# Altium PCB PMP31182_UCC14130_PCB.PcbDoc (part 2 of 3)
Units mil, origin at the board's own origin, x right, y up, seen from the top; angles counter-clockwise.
Board outline 4922 x 2399 mil, 4 copper layers (Top Layer, Signal Layer 1, Signal Layer 2, Bottom Layer), stack 77.9 mil thick; 154 components, 84 nets, 539 pads, 732 vias.

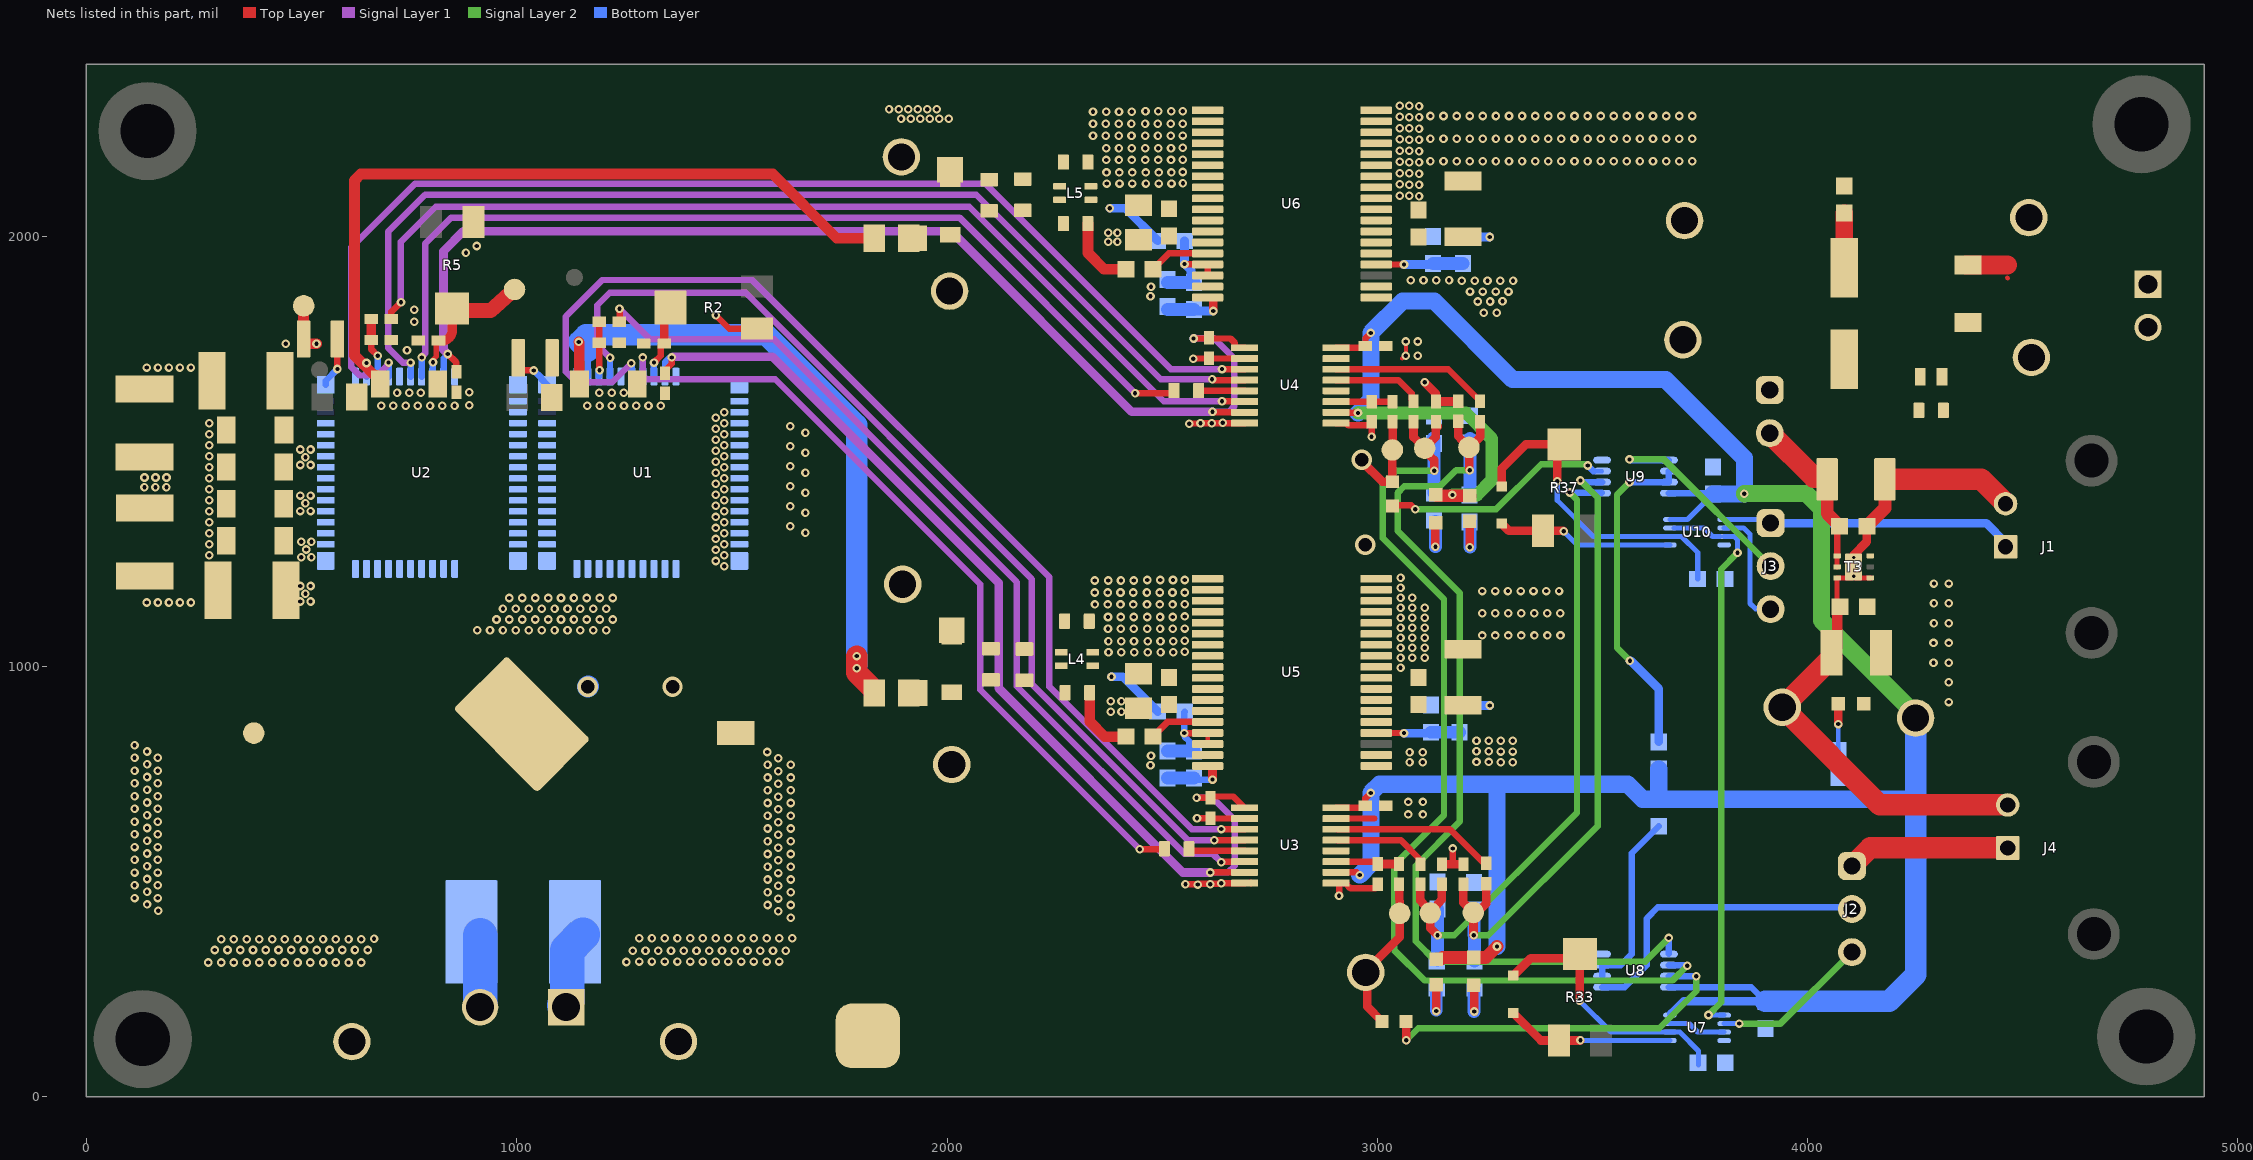
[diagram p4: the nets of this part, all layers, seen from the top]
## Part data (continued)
R7 R16: library part CMP-0026404-2, "RES, 49.9, 1%, 0.063 W, AEC-Q200 Grade 0, 0402", Manufacturer=Vishay-Dale, Power_W=63mW, Supplier Part Number 1=541-49.9LCT-ND, TempCo="100 ppm/C", Tolerance_%=1%, Value2=0.063W, Value_Code=49R9, ValueDisplayed=49.9
R8 R26: library part CMP-0022925-5, "RES, 22.0 k, 1%, 0.1 W, 0603", Manufacturer=Yageo, Power_W=100mW, Supplier Part Number 1=311-22.0KHRCT-ND, TempCo="100 ppm/C", Tolerance_%=1%, Value2=0.1W, Value_Code=22k0, ValueDisplayed=22.0k
R9 R18 R24 R27 R31 R32 R41: library part CMP-0089143-1, "0 Ohms Jumper 0.1W, 1/10W Chip Resistor 0603 (1608 Metric) Automotive AEC-Q200 Thick Film", Digikey Part Number=P0.0GCT-ND, Manufacturer=Panasonic, Mouser Part Number=667-ERJ-3GEY0R00V, Operating Temperature Range="-55°C to +155°C", Power_W=100mW, TempCo=-100/+600ppm/°C, Tolerance_%=5%
R10 R12 R14 R17 R21: library part CMP-0025797-4, "RES, 3.3 k, 5%, 0.1 W, AEC-Q200 Grade 0, 0603", Manufacturer=Vishay-Dale, Power_W=100mW, Supplier Part Number 1=541-3.3KGCT-ND, TempCo="200 ppm/C", Tolerance_%=5%, Value2=0.1W, Value_Code=3k30, ValueDisplayed=3.3k
R11 R28: library part CMP-0024313-3, "RES, 51.1 k, 0.1%, 0.1 W, 0603", Manufacturer="Yageo America", Power_W=100mW, TempCo="25 ppm/C", Tolerance_%=0.1%, Value2=0.1W, Value_Code=51k1, ValueDisplayed=51.1k
R13: library part CMP-0022714-3, "RES, 0.33, 1%, 0.1 W, AEC-Q200 Grade 0, 0603", Manufacturer=Panasonic, Power_W=100mW, Supplier Part Number 1=P.33AJCT-ND, TempCo="300 ppm/C", Tolerance_%=1%, Value2=0.1W, Value_Code=R330, ValueDisplayed=0.33
R22 R29: library part CMP-0022684-3, "RES, 10.0 k, 1%, 0.1 W, 0603", Manufacturer=Panasonic, Power_W=100mW, Supplier Part Number 1=P10.0KHCT-ND, TempCo="100 ppm/C", Tolerance_%=1%, Value2=0.1W, Value_Code=10k0, ValueDisplayed=10.0k
R23 R30: library part CMP-0024580-3, "RES, 10.2 k, 0.5%, 0.1 W, 0603", Manufacturer="Yageo America", Power_W=100mW, TempCo="50 ppm/C", Tolerance_%=0.5%, Value2=0.1W, Value_Code=10k2, ValueDisplayed=10.2k
R33 R37: library part CMP-0002062-2, "Trimmer, 5 K, 0.25 W, SMD", Manufacturer=Bourns, Supplier Part Number 1=3224X-1-502ECT-ND
R34 R38: library part CMP-0025697-4, "RES, 0, 5%, 0.1 W, AEC-Q200 Grade 0, 0603", Manufacturer=Vishay-Dale, Power_W=100mW, Supplier Part Number 1=541-0.0GCT-ND, TempCo="200 ppm/C", Tolerance_%=5%, Value2=0.1W, Value_Code=0000, ValueDisplayed=0
R35 R36: library part CMP-0082530-1, "RES, 100 k, 5%, 0.1 W, 0603", Manufacturer=Vishay-Dale, Power_W=100mW, Supplier Part Number 1=541-3992-1-ND, TempCo="200 ppm/C", Tolerance_%=5%, Value2=0.1W, Value_Code=100k
SH-J1 SH-J2 SH-J3: library part CMP-0003623-3, "Shunt, 100mil, Gold plated, Black", Alternate Manufacturer=3M, Alternate PartNumber=969102-0000-DA, Manufacturer=Samtec, Supplier Part Number 1=SAM8858-ND
T3: library part CMP-0086086-2, "150-mA High-Voltage Ultralow-IQ Low-Dropout Regulator, DRV0006A (WSON-6)", Alternate Manufacturer="Texas Instruments"
Top_FET_PWM: library part CMP-0055144-1, "Test Point, Compact, White, TH", Color=White, Manufacturer=Keystone, Supplier Part Number 1=36-5007-ND
TP1: library part CMP-0055153-1, "Test Point, Compact, SMT", Manufacturer=Keystone, Supplier Part Number 1=36-5016TR-ND
TP2: library part CMP-0003968-1, "Test Point, SMT", Manufacturer=Harwin, Supplier Part Number 1=952-2664-1-ND
U1 U2: library part CMP-0089968-1, "650-V 30-mΩ GaN FET with Integrated Driver and Protection", Manufacturer="Texas Instruments", Max Supply Voltage=18V, Min Supply Voltage=7.5V, Nominal Supply Current=540uA, Operating Temperature Range="-40°C to +125°C", Output Voltage=520V
U3 U4: library part CMP-0090469-1, "General Purpose Digital Isolator 2500Vrms 4 Channel 100Mbps 85kV/µs CMTI 16-SSOP (0.154\", 3.90mm Width)", Digikey Part Number=296-51207-1-ND, Manufacturer="Texas Instruments", Max Supply Voltage=5.5V, Min Supply Voltage=2.25V, Mouser Part Number=595-ISO7741FQDBQRQ1, Nominal Supply Current=1.5-18mA, Operating Temperature Range="-40°C to +125°C"
U5 U6: library part CMP-0089786-7, "2W, 24V-Vin, 25V-Vout, High-Efficiency, 5 kVRMS Isolated DC-DC Converter", Manufacturer="Texas Instruments", Max Supply Voltage=27V, Min Supply Voltage=21V, Operating Temperature Range="-40°C to +150°C", Output Voltage=18-25/2.5-25V, PartNumber=UCC14130DWNQ1
U7 U10: library part CMP-0051969-2, "Triple Schmitt-Trigger Inverter, DCU0008A (VSSOP-8)", F @ Nom Voltage(Max)(Mhz)=150, Generic Part Number=SN74LVC3G14, ICC @ Nom Voltage(Max)(mA)=0.01, Manufacturer="Texas Instruments", Operating Temperature Range="-40 to 125 C", Rating=Catalog, tpd @ Nom Voltage(Max)(ns)=9.2,5.7,5.4,4.3, Voltage(Nom)(V)=1.8,2.5,3.3,5
U8 U9: library part CMP-0051803-1, "Automotive Catalog Dual 2-Input Positive-AND Gate, DCT0008A, LARGE T&R", F @ Nom Voltage(Max)(Mhz)=150, Generic Part Number=SN74LVC2G08-Q1, ICC @ Nom Voltage(Max)(mA)=0.01, Manufacturer="Texas Instruments", Operating Temperature Range(C)="-40 to 85", Rating=Automotive, tpd @ Nom Voltage(Max)(ns)=9,5.1,4.7,3.8, Voltage(Nom)(V)=1.8,2.5,3.3,5

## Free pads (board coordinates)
  round 50 smd paste-30: 1(389,845) 1(505,1838) 1(995,1876) 1(3035,1503) 1(3052,426) 1(3110,1507) 1(3123,427) 1(3213,1509) 1(3223,428)
  round 40 smd paste-30: 1(542,1689) 1(1134,1904)
  round 228.35 hole 125.98: 2(131,134) 2(142,2244) 2(4776,2260) 2(4787,140)
  rect 60x60 smd: 3(1923,1995) 3(1925,938) 3(2007,2154) 3(2011,1084)
  rrect50% 150x150 smd: Load_GND(1816.25,141.5)

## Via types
v1: diameter 20, hole 10, Top Layer to Bottom Layer, tented both sides, 726 vias
v2: diameter 47.24, hole 31.5, Top Layer to Bottom Layer, 4 vias
v3: diameter 19.68, hole 7.87, Top Layer to Bottom Layer, 2 vias

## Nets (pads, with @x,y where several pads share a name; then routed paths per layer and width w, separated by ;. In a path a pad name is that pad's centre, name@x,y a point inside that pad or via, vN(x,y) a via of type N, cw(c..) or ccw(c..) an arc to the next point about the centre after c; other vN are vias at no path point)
5V: C9.1 C26.1 C41.2 C44.2 C48.1 C53.1 HS_FLT.1 HS_OC.1 LDO5V.1 LDO.1 LS_FLT.1 LS_OC.1 R35.1 R36.2 T3.6 U3.10 U3.16 U4.10 U4.16 U7.8 U8.8 U9.8 U10.8 | length 6856.6
  Top Layer w15: U3.10@2904.08,521.5 2952.5,521.5 v1(2959,515) ; U3.16@2904.08,671.5 2967.88,671.5 C26.1@2972.38,676 2972.38,693.38 v1(2985,706) ; U4.16@2904.33,1740.75 U4.16@2904.08,1740.5 2962.26,1740.5 C9.1@2969.57,1747.81 ; U4.10@2905.08,1590.5 2905.65,1589.93 2954.07,1589.93 v1(2955,1589) ; C9.1@2972.57,1744.81 2972.57,1762.57 v1(2985,1775)
  Top Layer w30: HS_FLT.1@3137,319.53 3137.75,320.28 3148.03,320.28 3151.24,323.48 HS_OC.1@3224,323.48 3252.48,323.48 v1(3278,349) ; LS_OC.1@3137.95,1396.53 v1@3172.57,1396.53 ; v1@3176.48,1396.53 LS_FLT.1@3215,1396.53
  Signal Layer 2 w30: v1@2956,1590 v1(2955,1589) 3206,1589 3266,1529 3266,1433 3231.48,1398.48 v1(3174.52,1398.48)
  Signal Layer 2 w40: v1(3853,1401) 3854,1402 3997,1402 4032,1367 4032,1107 4251,888 LDO5V.1@4251,880
  Bottom Layer w10: 4045.91,221.5 4045.91,221.65
  Bottom Layer w12: U10.8@3680.02,1341.37 3720.87,1341.37 C44.2@3780,1400.5
  Bottom Layer w15: U8.8@3677.76,254.61 3868.88,254.61 C41.2@3902,221.5 ; U9.8@3677.76,1402.61 C44.2@3777.89,1402.61
  Bottom Layer w20: R35.1@3654,693.5 3660.7,693.5 R35.1@3662.7,691.5 ; U7.8@3683.74,193.26 3711.98,221.5 C41.2@3902,221.5 ; 4245.5,691.5 4251,697
  Bottom Layer w40: v1(2955,1589) 2985,1619 v1(2985,1775) 3059,1849 3132.19,1849 3314.69,1666.5 3670.5,1666.5 3853,1484 v1(3853,1401) ; v1(2959,515) 2985,541 v1@2985,701.41 ; v1(2985,706) 3005,726 3278,726 ; v1(3278,349) 3278,726 ; R35.1@3654,691.5 3616.5,691.5 3582,726 3278,726 ; R35.1@3654,693.5 R36.2@3654,761.5 ; R35.1@3662.7,691.5 4245.5,691.5 ; C44.2@3780,1400.5 v1@3852.5,1400.5
  Bottom Layer w50: C41.2@3902,221.5 4045.91,221.5 4189.5,221.5 4251,283 4251,697 LDO5V.1@4251,880
  other v1: 4328,917.08 4328,962.91 4292.48,1008.75 4328,1008.75 4292.48,1054.58 4328,1054.58 4293.48,1100.41 4328,1100.41 4293.48,1146.46 4328,1146.46 4293.48,1192.46 4328,1192.46
5V_H: C2.1 C10.1 U1.51 U3.1 U3.7 | length 2471
  Top Layer w15: C2.1@1344.59,1681.62 1348.9,1685.93 1348.9,1691.9 1360.45,1703.45 v1(1360.45,1718.06) ; v1(2580,695) 2580.19,694.81 2611.81,694.81 C10.1@2612,694.62 ; C10.1@2612,697.62 2665.36,697.62 U3.1@2691.48,671.5 ; v1@2612.5,521.5 U3.7@2691.48,521.5
  Signal Layer 1 w15: v1(2580,695) 2617.08,695 2669,643.08 2669,537 2653,521 v1(2612,521)
  Signal Layer 1 w20: v1(1360.45,1718.06) 1362.37,1719.97 1369.44,1719.97 1594,1720 2120,1194 2120,949 2548,521 v1(2612,521)
  Bottom Layer w15: U1.51@1344.59,1673.4 1344.59,1706.59 1355.1,1717.1 1359.5,1717.1 v1(1360.45,1718.06)
5V_L: C12.1 C27.1 U2.51 U4.1 U4.7 | length 2820.4
  Top Layer w15: v1(840,1726) 860,1706 C12.1@860,1684.62 ; v1(2573,1762) 2607.76,1762 C27.1@2609,1763.24 2612.07,1763.24 2613.31,1762 2658.7,1762 2669.13,1751.57 2669.13,1741.07 2669.7,1740.5 U4.1@2691.48,1740.5 ; v1(2617,1592) 2618.35,1592 2619.85,1590.5 U4.7@2691.48,1590.5
  Signal Layer 1 w15: v1@2574,1763 2620,1763 2668,1715 2668,1605.01 2654.99,1592 v1(2617,1592)
  Signal Layer 1 w20: v1(840,1726) 830,1736 830,1965 876,2011 2010,2011 2429,1592 v1(2617,1592) ; v1(2573,1762) v1@2574,1763
  Bottom Layer w15: U2.51@830.17,1673.4 830.17,1716.17 v1(840,1726)
15V: 15VIN.1 C25.1 J6.2 L3.1 R32.1
15V_F: 15VINF.1 C8.1 C22.1 C24.1 C33.1 C34.1 J7.1 L3.2 R8.2 R26.2 R32.2 U5.6 U5.7 U6.6 U6.7 | length 133
  Bottom Layer w10: R8.2@3191,909.99 R8.2@3191.84,909.15 ; R26.2@3199,2007.5 R26.2@3200.5,2006
  Bottom Layer w20: R8.2@3191.84,909.15 v1(3261,909.15) ; R26.2@3200.5,1998 v1(3261,1998)
Bot_FET_FAULT: C52.1 C57.1 pad.1@3213,1509 R14.1 R40.2 U8.5 | length 2318.5
  Top Layer w20: C57.1@3188,1569.38 3188,1535.24 3204.07,1517.24 pad.1@3206.97,1514.34 ; pad.1@3213,1509 3214,1508 3214,1457 v1(3215,1456) ; pad.1@3215,1510.85 3239,1533 R40.2@3239,1569
  Signal Layer 2 w15: v1(3215,1456) 3183,1456 3145.49,1418.49 3062.49,1418.49 3047,1403 3047,1315 3192,1170 3192,640 3089,537 3089,361.5 3136.5,314 3622.38,314 v1@3677.19,368.81
  Bottom Layer w10: v1(3677,369) v1@3677.38,368.62 ; U8.5@3677.38,331.76 U8.5@3677.76,331.39
  Bottom Layer w15: U8.5@3677.38,331.76 v1@3677.38,368.62
  Bottom Layer w30: R14.1@3215,1398.5 v1(3215,1456) C52.1@3215,1529.5
Bot_FET_OC: C55.1 C56.1 pad.1@3110,1507 R17.1 R39.2 U8.6 | length 2435.4
  Top Layer w20: R39.2@3084,1569 3084,1533 pad.1@3110,1507 ; v1(3132,1455) 3132,1479.73 3110,1501.73 pad.1@3110,1507 ; C56.1@3140.7,1557.02 C56.1@3136,1568.38 3136,1533 pad.1@3110,1507
  Signal Layer 2 w15: v1(3132,1455) 3044,1455 3013,1424 3013,1298 3155,1156 3155,654 3039,538 3039,341 3110,270 3686,270 v1(3720,304)
  Bottom Layer w12: v1@3716.04,305.8 3717.84,304 v1(3720,304)
  Bottom Layer w15: U8.6@3677.76,305.8 v1@3716.04,305.8
  Bottom Layer w30: C55.1@3131,1530.5 3132,1529.5 v1(3132,1455) R17.1@3132,1403
Bot_FET_PWM: pad.1@3035,1503 R16.1 R38.2 | length 230.1
  Top Layer w20: v2@2964,1477 3012,1429 R38.2@3035,1429 pad.1@3035,1503 3035.5,1537.5 R16.1@3035.5,1568.26
  other v2: 2964,1480
Bot_FET_TEMP: U4.12
ENAH: R8.1 R22.2 U5.4 | length 192
  Top Layer w10: v1@3061.75,845.25 v1(3062,845)
  Top Layer w15: U5.4@2997.31,845.25 v1@3061.75,845.25
  Bottom Layer w10: R22.2@3113.54,845 R22.2@3120.04,851.5
  Bottom Layer w20: v1(3062,845) R22.2@3113.54,845
  Bottom Layer w30: R22.2@3124.54,847 R8.1@3191,847
ENAL: R26.1 R29.2 U6.4 | length 202.7
  Top Layer w15: U6.4@2997.31,1934 v1(3062,1934)
  Bottom Layer w10: R29.2@3126.5,1934 R29.2@3129,1936.5
  Bottom Layer w20: v1(3062,1934) R29.2@3126.5,1934
  Bottom Layer w30: R29.2@3129,1936.5 R26.1@3199,1936.5
FAULT_H: U1.46 U3.4 | length 2361.7
  Top Layer w10: U3.4@2705.23,595.25 U3.4@2706.48,596.5
  Top Layer w15: v1@2621.5,596.5 U3.4@2691.48,596.5
  Signal Layer 1 w15: v1(1217,1717) 1187,1747 1187,1839 1216,1868 1532,1868 2197,1203 2197,959 2560,596 v1(2621,596)
  Bottom Layer w15: U1.46@1216.64,1673.4 1216.82,1673.58 1216.82,1712.82 v1@1217,1713
FAULT_L: U2.46 U4.3 | length 2734.9
  Top Layer w15: v1@2639.5,1690.5 U4.3@2691.48,1690.5
  Signal Layer 1 w15: v1(702.21,1706) 702.21,1704.65 699.71,1702.15 699.71,1700.07 675.65,1676 635,1676 616,1695 616,1974 764,2122 2089,2122 2520,1691 v1(2639,1691)
  Bottom Layer w15: U2.46@702.21,1673.4 v1(702.21,1706)
FBVDDH: C30.1 R11.1 R23.2 U5.33 U5.34 | length 243.9
  Top Layer w10: v1(2551,845) v1@2551.13,845.13 ; U5.33@2605.46,845.13 U5.33@2605.58,845.25 U5.34@2605.58,819.66
  Top Layer w15: v1@2551.13,845.13 U5.33@2605.46,845.13
  Bottom Layer w15: R11.1@2552.5,895 2551,893.5 v1(2551,845) 2551.96,844.04 2551.96,837.04 2562.82,826.18 2562.82,814.68 C30.1@2574,803.5
  Bottom Layer w30: R23.2@2512,803.5 2562.82,803.5 C30.1@2574,803.5
FBVDDL: C37.1 R28.1 R30.2 U6.33 U6.34 | length 244.9
  Top Layer w15: v1(2552,1935) 2552.5,1934.5 2605.5,1934.5 2606,1934 U6.34@2606,1908.41
  Bottom Layer w20: R28.1@2552.5,1989 2552,1988.5 v1(2552,1935) 2567,1920 C37.1@2567,1892.5
  Bottom Layer w30: R30.2@2512,1892.5 C37.1@2574,1892.5
GND_HV: C11.1 C12.2 C13.1 C15.2 C16.2 C17.2 C18.2 C19.2 C20.2 C21.2 C23.1 C27.2 C35.2 C36.2 C38.2 C43.1 C49.2 D2.2 GNDHV.1 ISO15VGND.1 J5.1 L2.1 L5.1 pad.1@505,1838 pad.3@2007,2154 pad.Load_GND R5.1 R31.2 TP2.1 U2.17 U2.18 U2.19 U2.20 U2.21 U2.22 U2.23 U2.24 U2.25 U2.26 U2.27 U2.28 U2.29 U2.30 U2.31 U2.32 U2.33 U2.34 U2.35 U2.36 U2.37 U2.38 U2.39 U4.2 U4.8 | length 566.5
  Top Layer w10: C20.2@453,1138.74 C20.2@453,1159 ; pad.1@504.63,1834.63 pad.1@505,1835 ; v1(2563,1564) v1@2563.5,1564.5 ; v1@2588.5,1564.5 v1(2589,1565)
  Top Layer w15: v1@2563.5,1564.5 v1@2588.5,1564.5 ; v1(2572,1715) 2572.5,1715.5 U4.2@2691.48,1715.5 ; v1(2589,1565) v1(2615,1565) 2615.5,1565.5 2640.5,1565.5 v1(2641,1566) ; v1@2641.5,1565.5 U4.8@2691.48,1565.5
  Top Layer w25: pad.1@505,1835 504.63,1824.63 L2.1@504.63,1761 504.63,1750 v1(534.63,1750)
  Bottom Layer w80: J5.1@1110,213 1117.32,220.32 1117.32,340.32 C49.2@1154,377
  other v1: 1255,313 1284.62,314 1314.23,314 1343.85,314 1373.46,314 1403.08,314 1432.69,314 1462.31,314 1491.92,314 1521.54,314 1551.15,314 1580.77,314 1610.38,314 1269.81,339 1299.42,339 1329.04,339 1358.65,339 1388.27,339 1417.88,339 1447.5,339 1477.11,339 1506.73,339 1536.34,339 1565.96,339 1595.57,339 1625.19,339 1284.62,368 1314.23,368 1343.85,368 1373.46,368 1403.08,368 1432.69,368 1462.31,368 1491.92,368 1521.54,368 1551.15,368 1580.77,368 1610.38,368 1640,368 1637,416 1608,430.81 1583,445.62 1637,445.62 1608,460.43 1583,475.23 1637,475.23 1608,490.04 1583,504.85 1637,504.85 1608,519.66 1583,534.46 1637,534.46 1608,549.27 1583,564.08 1637,564.08 1608,578.89 1583,593.69 1637,593.69 1608,608.5 1583,623.31 1637,623.31 1608,638.12 1583,652.92 1637,652.92 1608,667.73 1583,682.54 1637,682.54 1608,697.35 1583,712.15 1637,712.15 1608,726.96 1583,741.77 1637,741.77 1608,756.58 1583,771.38 1637,771.38 1608,786.19 1582,801 497,1150.87 521,1150.87 509,1168.87 497,1186.87 521,1186.87 499,1253.64 523,1253.64 511,1271.64 499,1289.64 523,1289.64 497,1361 521,1361 509,1379 497,1397 521,1397 134.82,1416 160.41,1416 186,1416 135,1439 160.59,1439 186.18,1439 497,1468 521,1468 509,1486 497,1504 521,1504 685,1606 713.43,1606 741.86,1606 770.29,1606 798.71,1606 827.14,1606 855.57,1606 890,1607 722,1636 750,1636 777,1636 890,1637 745,1735 463,1750 762,1801 762,1829 882,1961 907,1977 1893.24,2272.79 1915.44,2272.79 1937.64,2272.79 1959.84,2272.79 1982.04,2272.79 2004.24,2272.79 1865.4,2295 1887.6,2295 1909.8,2295 1932,2295 1954.2,2295 1976.4,2295
  other v2: 1362.2,953
GND_LV: C6.2 C9.2 C14.1 C22.2 C24.2 C25.2 C26.2 C33.2 C34.2 C39.2 C40.2 C41.1 C44.1 C45.2 C46.2 C47.2 C48.2 C50.2 C51.2 C52.2 C53.2 C54.1 C55.2 C56.2 C57.2 GND_LV.1 GNDLV.1 GNDLVF.1 J1.2 J4.2 J6.1 R13.1 R21.1 R22.1 R29.1 T3.3 T3.4 T3.7@4107,1231.35 U3.9 U3.15 U4.9 U4.15 U5.1 U5.2 U5.5 U5.8 U5.9 U5.10 U5.11 U5.12 U5.13 U5.14 U5.15 U5.16 U5.17 U5.18 U6.1 U6.2 U6.5 U6.8 U6.9 U6.10 U6.11 U6.12 U6.13 U6.14 U6.15 U6.16 U6.17 U6.18 U7.4 U8.4 U9.4 U10.4 | length 2299.5
  Top Layer w10: U3.9@2904.08,496.5 2907.93,496.5 U3.9@2911,493.43 ; C14.1@2986,1568.26 C14.1@2986.63,1567.63 ; C6.2@3001,489.56 C6.2@3001,493.5 ; 3057.8,1715.5 3064.29,1722 v1(3066,1722) 3067,1722 3066.5,1722.5 3066.5,1754.5 v1(3066,1755) ; 3175,543.97 3178.35,540.62 ; C48.2@4051.91,1035.63 C48.2@4055.91,1031.63 C48.2@4055.91,1019.91 ; C53.2@4068.61,1145.52 C53.2@4075.5,1138.63 ; T3.7@4103.06,1205.76 v3(4107,1209.69) T3.7@4110.94,1205.76 ; v3(4107,1253) T3.7@4113.95,1253 ; 4464.07,1902.93 4465,1902
  Top Layer w12: C53.2@4068.61,1145.52 T3.3@4068.61,1205.76 T3.7@4103.06,1205.76 ; T3.7@4110.94,1205.76 T3.4@4145.39,1205.76
  Top Layer w15: U3.15@2904.08,646.5 2993,646.5 ; U4.9@2904.08,1565.5 2927.5,1565.5 2933,1560.01 2981.69,1560.01 2986,1564.32 C14.1@2986,1568.26 ; U3.9@2907.93,496.5 2927.5,496.5 2928.08,495.93 2928.08,493.79 2937.86,484 2995.44,484 C6.2@3001,489.56 ; v1(2911,467) U3.9@2911,493.43 ; v1(2986.63,1534) C14.1@2986.63,1567.63 ; 3175,543.97 v1(3175,577)
  Top Layer w20: v1(3110,1660) 3110.37,1660 3136,1634.37 C56.2@3136,1615.62 3187,1615.62 C57.2@3188,1616.62 ; C40.2@3150,540.62 3178.35,540.62 C39.2@3200,540.62 ; T3.7@4107,1231.35 v3(4107,1253) 4107,1259.01 4137.5,1289.5 C47.2@4137.5,1325.63
  Top Layer w25: C48.2@4055.91,1031.63 4069,1044.72 4069,1132.43 4075.2,1138.63 C53.2@4075.5,1138.63
  Top Layer w30: C47.2@4137.5,1325.63 4179.35,1367.49 C54.1@4179.35,1434.63
  Top Layer w45: C25.2@4368,1932.93 4464.07,1932.93
  Top Layer w50: C48.2@4055.91,1019.91 GND_LV.1@3941,905 4168,678 J4.2@4465,678 ; C54.1@4179.35,1434.63 4403.37,1434.63 J1.2@4460,1378
  other v1: 3072,656 3106,656 3072,685 3106,685 3075,777 3105.33,777 3286.86,777.14 3315,777.14 3230.58,778 3258.72,778 3075,800.5 3105.33,800.5 3286.86,802.07 3315,802.07 3230.58,802.5 3258.72,802.5 3230.58,827 3258.72,827 3286.86,827 3315,827 3054,997 3054,1020.22 3081,1020.22 3110,1020.22 3054,1043.44 3081,1043.44 3110,1043.44 3054,1066.67 3081,1066.67 3110,1066.67 3244.02,1072 3274.28,1072 3304.55,1072 3334.81,1072 3365.07,1072 3395.34,1072 3425.6,1072 3054,1089.89 3081,1089.89 3110,1089.89 3054,1113.11 3081,1113.11 3110,1113.11 3244.02,1123.5 3274.19,1123.5 3304.35,1123.5 3334.51,1123.5 3364.68,1123.5 3394.84,1123.5 3425.01,1123.5 3054,1136.33 3081,1136.33 3110,1136.33 3054,1159.56 3081,1159.56 3244.02,1175 3273.74,1175 3303.47,1175 3333.19,1175 3362.91,1175 3392.64,1175 3422.36,1175 3054,1182.78 3054,1206 3094,1722 3094,1755 3247.63,1822 3277.24,1822 3233.44,1848 3262.05,1848 3290.9,1848.5 3215.49,1871 3245.24,1871 3275,1871 3304.76,1871 3196.54,1896 3226.29,1896 3256.03,1896 3285.77,1896 3315.51,1896 3077.58,1897.5 3107.32,1897.5 3137.06,1897.5 3166.8,1897.5 3097,2092.87 3052,2094 3074.51,2093.44 3097,2119.01 3052,2120.14 3074.51,2119.58 3097,2145.15 3074.51,2145.72 3052,2146.28 3074.51,2171.86 3097,2171.29 3052,2172.42 3123.44,2174 3153.87,2174 3184.3,2174 3214.73,2174 3245.15,2174 3275.58,2174 3306.01,2174 3336.44,2174 3366.87,2174 3397.3,2174 3427.72,2174 3458.15,2174 3488.58,2174 3519.01,2174 3549.44,2174 3579.87,2174 3610.3,2174 3640.72,2174 3671.15,2174 3701.58,2174 3732.01,2174 3074.51,2198 3097,2197.43 3052,2198.57 3074.51,2224.15 3097,2223.58 3052,2224.71 3123.44,2226 3153.87,2226 3184.3,2226 3214.73,2226 3245.15,2226 3275.58,2226 3306.01,2226 3336.44,2226 3366.87,2226 3397.3,2226 3427.72,2226 3458.15,2226 3488.58,2226 3519.01,2226 3549.44,2226 3579.87,2226 3610.3,2226 3640.72,2226 3671.15,2226 3701.58,2226 3732.01,2226 3097,2249.72 3052,2250.85 3074.51,2250.29 3097,2275.86 3052,2276.99 3074.51,2276.43 3123.44,2279 3153.87,2279 3184.3,2279 3214.73,2279 3245.15,2279 3275.58,2279 3306.01,2279 3336.44,2279 3366.87,2279 3397.3,2279 3427.72,2279 3458.15,2279 3488.58,2279 3519.01,2279 3549.44,2279 3579.87,2279 3610.3,2279 3640.72,2279 3671.15,2279 3701.58,2279 3732.01,2279 3097,2302 3052,2303.13 3074.51,2302.57
  other v2: 2972,1283
HVBUS: C15.1 C16.1 C17.1 C18.1 C19.1 C20.1 C21.1 C38.1 C49.1 HVIN.1 J5.2 pad.1@389,845 U1.1 U1.2 U1.3 U1.4 U1.5 U1.6 U1.7 U1.8 U1.9 U1.10 U1.11 U1.12 U1.13 U1.14 U1.15 U1.16 | length 169.8
  Bottom Layer w10: C49.1@907.53,383 C49.1@909.47,381.06
  Bottom Layer w80: J5.2@915,208 C49.1@915,375.06
  other v1: 283.5,312 313.12,312 342.73,312 372.35,312 401.96,312 431.58,312 461.19,312 490.81,312 520.42,312 550.04,312 579.65,312 609.27,312 638.88,312 298.31,341 327.92,341 357.54,341 387.15,341 416.77,341 446.38,341 476,341 505.62,341 535.23,341 564.85,341 594.46,341 624.08,341 653.69,341 313.12,366 342.73,366 372.35,366 401.96,366 431.58,366 461.19,366 490.81,366 520.42,366 550.04,366 579.65,366 609.27,366 638.88,366 668.5,367 167,432 141,446.81 112,461.62 166,461.62 141,476.42 112,491.23 166,491.23 141,506.04 112,520.85 166,520.85 141,535.65 112,550.46 166,550.46 141,565.27 112,580.08 166,580.08 141,594.88 112,609.69 166,609.69 141,624.5 112,639.31 166,639.31 141,654.11 112,668.92 166,668.92 141,683.73 112,698.54 166,698.54 141,713.34 112,728.15 166,728.15 141,742.96 112,757.77 166,757.77 141,772.57 112,787.38 166,787.38 141,802.19 112,817 140.59,1148.52 166.18,1148.52 191.77,1148.52 217.36,1148.52 242.95,1148.52 1482.43,1232.46 1462.43,1245.05 285.22,1258.05 1482.43,1258.05 1462.43,1270.64 285.22,1283.64 1482.43,1283.64 1462.43,1296.23 285.22,1309.23 1482.43,1309.23 1462.43,1321.82 285.22,1334.82 1482.43,1334.82 1462.43,1347.41 285.22,1360.41 1482.43,1360.41 1462.43,1373 285.22,1386 1482.43,1386 1462.43,1398.59 285.22,1411.59 1482.43,1411.59 1462.43,1424.18 285.22,1437.18 1482.43,1437.18 1462.43,1449.77 285.22,1462.77 1482.43,1462.77 1462.43,1475.36 285.22,1488.36 1482.43,1488.36 1462.43,1500.95 285.22,1513.95 1482.43,1513.95 1462.43,1526.54 285.22,1539.54 1482.43,1539.54 1462.43,1552.13 285.22,1565.13 1482.43,1565.13 1462.43,1577.73 1482.43,1590.73 140.59,1694.48 166.18,1694.48 191.77,1694.48 217.36,1694.48 242.95,1694.48
IN_H: C5.2 R6.2 U1.45 | length 116.5
  Top Layer w15: C5.2@1190.39,1749.38 1191.99,1747.78 1191.99,1688.78 v1(1192.6,1688.17) ; C5.2@1191.38,1752 R6.2@1191.38,1791
  Bottom Layer w15: U1.45@1191.05,1673.4 1191.05,1686.62 v1(1192.6,1688.17)
IN_L: C23.2 R15.2 U2.45 | length 139.7
  Top Layer w15: C23.2@661.47,1758.91 661.47,1737.53 v1(677,1722)
  Top Layer w22: C23.2@661.47,1758.91 R15.2@661.47,1807
  Bottom Layer w15: U2.45@676.62,1673.4 v1@676.62,1721.62
ISO_15V_H: C28.1 C29.1 D1.1 ISO15VH.1 L4.2 pad.3@1925,938 R1.1 R9.2
ISO_15V_H_B: C4.2 C7.2 L4.3 R4.2 R9.1 R11.2 U5.28 U5.29 | length 306
  Top Layer w25: R9.1@2331.54,939 2331.54,871.79 2366.54,836.79 R4.2@2415.29,836.79
  Bottom Layer w20: v1(2382.35,975.7) 2408.8,975.7 R11.2@2489.5,895
ISO_15V_L: C35.1 C36.1 D2.1 ISO15VL.1 L5.2 pad.3@1923,1995 R3.1 R27.2
ISO_15V_L_B: C31.2 C32.2 L5.3 R25.2 R27.1 R28.2 U6.28 U6.29 | length 315
  Top Layer w25: R27.1@2327.54,2029 2327.54,1960.46 2365,1923 R25.2@2415.5,1923
  Bottom Layer w20: v1(2378,2065) 2413.5,2065 R28.2@2489.5,1989
ISO_RET_H_B: C4.1 C7.1 C30.2 L4.4 R23.1 R24.1 U5.19 U5.20 U5.21 U5.22 U5.23 U5.24 U5.25 U5.26 U5.27 U5.30 U5.31 U5.35 U5.36 | length 129.5
  Top Layer w20: v1(2617,737) U5.36@2617,760
  Bottom Layer w10: C30.2@2574,740.5 C30.2@2577.5,737
  Bottom Layer w15: C30.2@2577.5,737 v1(2617,737)
  Bottom Layer w30: R23.1@2512,740.5 C30.2@2574,740.5
  other v1: 2473,770.5 2474,792.5 2380.81,894.7 2405.35,894.7 2380.81,918.7 2405.35,918.7 2375.35,1032.7 2405.11,1032.7 2434.86,1032.7 2466.59,1032.7 2496.35,1032.7 2526.11,1032.7 2552.59,1033.7 2375.11,1058.7 2404.86,1058.7 2434.62,1058.7 2466.35,1058.7 2496.11,1058.7 2525.86,1058.7 2552.35,1059.7 2374.11,1087.7 2403.86,1087.7 2433.62,1087.7 2465.35,1087.7 2495.11,1087.7 2524.86,1087.7 2552.35,1087.9 2374.11,1114.7 2403.86,1114.7 2433.62,1114.7 2465.35,1114.7 2495.11,1114.7 2524.86,1114.7 2552.35,1116.1 2343.69,1144.05 2373.45,1144.05 2403.21,1144.05 2432.96,1144.05 2464.69,1144.05 2494.45,1144.05 2524.21,1144.05 2552.35,1144.3 2343.59,1171.7 2373.35,1171.7 2403.11,1171.7 2432.86,1171.7 2464.59,1171.7 2494.35,1171.7 2524.11,1171.7 2552.35,1171.7 2343.59,1199.7 2374.35,1199.7 2404.11,1199.7 2433.86,1199.7 2465.59,1200.7 2495.35,1200.7 2525.11,1200.7 2552.35,1200.7
ISO_RET_L_B: C31.1 C32.1 C37.2 L5.4 R30.1 R31.1 U6.19 U6.20 U6.21 U6.22 U6.23 U6.24 U6.25 U6.26 U6.27 U6.30 U6.31 U6.35 U6.36 | length 152.5
  Top Layer w10: U6.36@2606,1857.23 2615.14,1857.23 U6.36@2619,1853.37
  Top Layer w20: v1(2619,1826) U6.36@2619,1853.37
  Bottom Layer w20: C37.2@2570.5,1826 v1(2619,1826)
  Bottom Layer w30: R30.1@2512,1829.5 C37.2@2574,1829.5
  other v1: 2473,1860 2474,1882 2374.46,1987 2396,1987 2374.46,2008 2396,2008 2371,2122 2400.76,2122 2430.51,2122 2462.24,2122 2492,2122 2521.76,2122 2548.24,2123 2370.76,2148 2400.51,2148 2430.27,2148 2462,2148 2491.76,2148 2521.51,2148 2548,2149 2369.76,2177 2399.51,2177 2429.27,2177 2461,2177 2490.76,2177 2520.51,2177 2548,2177.2 2369.76,2204 2399.51,2204 2429.27,2204 2461,2204 2490.76,2204 2520.51,2204 2548,2205.4 2339.34,2233.35 2369.1,2233.35 2398.86,2233.35 2428.61,2233.35 2460.34,2233.35 2490.1,2233.35 2519.86,2233.35 2548,2233.6 2339.24,2261 2369,2261 2398.76,2261 2428.51,2261 2460.24,2261 2490,2261 2519.76,2261 2548,2261 2339.24,2289 2370,2289 2399.76,2289 2429.51,2289 2461.24,2290 2491,2290 2520.76,2290 2548,2290
NC_PGND1: U2.43
NC_PGND2: U2.47
NC_PGND3: U2.52
NC_SW1: U1.43
NC_SW2: U1.47
NC_SW3: U1.52
NetC1_1: C1.1 R1.2 U1.44 | length 1588.9
  Top Layer w25: v1(1144,1754) 1145.07,1752.93 C1.1@1145.07,1656
  Top Layer w50: v1(1790,1024) v1(1790,996) 1790,985.5 1831,944.5 R1.2@1831,938
  Bottom Layer w15: U1.44@1165.46,1673.4 1165.46,1732.54
  Bottom Layer w50: 1165.46,1732.54 v1(1144,1754) 1161,1771 1580,1771 1790,1561 v1(1790,1024) v1@1790,1003
NetC6_1: C6.1 R7.2 U3.11 | length 149.7
  Top Layer w15: U3.11@2904.08,546.5 2996.69,546.5 3001,542.19 C6.1@3001,540.75
  Top Layer w20: C6.1@3001,540.75 R7.2@3050.5,540.75
NetC8_2: C8.2 R13.2 | length 127.2
  Top Layer w40: C8.2@4085,1926.3 R13.2@4085,2053.5
NetC11_2: C11.2 R3.2 U2.44 | length 1807.5
  Top Layer w25: C11.2@683.03,1656 683.03,1665.84 672.38,1676.5 669.18,1676.5 623,1722.68 623,2129.36 637.64,2144 1595,2144 1744,1995 R3.2@1831,1995
  Bottom Layer w15: U2.44@651.03,1673.4 v1@651.03,1705
  other v1: 651.03,1705.08
NetC14_2: C14.2 R16.2 U4.11 | length 132.4
  Top Layer w15: U4.11@2904.08,1615.5 C14.2@2987,1615.5 ; C14.2@2986,1615.5 R16.2@3035.5,1615.5
NetC42_1: C42.1 R2.2 U1.50 | length 169
  Top Layer w15: v1(1319,1706.08) 1335,1722.08 C42.1@1335,1745.69
  Top Layer w20: C42.1@1342.62,1750 1342.62,1819.02 R2.2@1357.61,1834
  Bottom Layer w15: U1.50@1319,1673.4 v1@1319,1706
NetC43_2: C43.2 pad.1@995,1876 R5.2 U2.50 | length 341.4
  Top Layer w12: v1@805.12,1708.79 807.11,1710.78 807.11,1714.22 813,1720.11 813,1751.76 C43.2@818.24,1757
  Top Layer w22: C43.2@818.24,1757 826.62,1757 ccw(c826.62,1780.38) 850,1780.38 R5.2@850,1827
  Top Layer w35: R5.2@850,1827 939,1827 pad.1@995,1876
  Bottom Layer w15: U2.50@804.58,1673.4 v1@804.58,1706
  other v1: 805.58,1707.08
NetC45_1: C45.1 D11.1 R33.2 U7.6 | length 640.4
  Top Layer w20: D11.1@3316,281.31 3356.69,322 3461.61,322 R33.2@3470,330.39 ; v1(3470,223) 3470,322 R33.2@3470,330.39 ; R33.2@3471,331.39 R33.2@3470,330.39
  Bottom Layer w12: v1(3470,223) 3542.84,150.16 U7.6@3680.02,150.16 3702.84,150.16 3746.5,106.5 C45.1@3746.5,74
NetC46_1: C46.1 D12.1 R37.2 U10.6 | length 785.4
  Top Layer w20: D12.1@3289,1418.31 3289,1460 3344.89,1515.89 R37.2@3434.5,1515.89 3418,1499.39 v1(3418,1430)
  Bottom Layer w12: v1(3418,1430) 3418,1386 3502,1302 U10.6@3680.02,1302 3707,1302 3744.5,1264.5 C46.1@3744.5,1203
NetC47_1: C47.1 C54.2 J7.2 T3.1 T3.2 | length 395.7
  Top Layer w12: T3.2@4068.61,1231.35 T3.1@4068.61,1256.94
  Top Layer w15: T3.1@4068.61,1256.94 C47.1@4068.61,1319.74
  Top Layer w20: C54.2@4040.13,1440 C54.2@4045.5,1434.63 ; C47.1@4068.61,1319.74 C47.1@4074.5,1325.63
  Top Layer w30: C54.2@4045.5,1434.63 4045.5,1354.64 C47.1@4074.5,1325.63
  Top Layer w50: J7.2@3912,1542 4014,1440 C54.2@4040.13,1440
NetD11_2: D11.2 R33.1 U7.5 | length 390.9
  Top Layer w20: D11.2@3316,194.69 3380.09,130.61 R33.1@3421.79,130.61 3471.61,130.61 v1(3472,131)
  Bottom Layer w12: v1(3472,131) 3472.53,130.47 U7.5@3680.02,130.47
NetD12_2: D12.2 R37.1 U10.5 | length 411.5
  Top Layer w20: D12.2@3289,1331.69 3305.59,1315.11 R37.1@3385.29,1315.11 3431.89,1315.11 v1(3433,1314)
  Bottom Layer w12: v1(3433,1314) 3464.68,1282.32 U10.5@3680.02,1282.32
NetHS_FLT_2: HS_FLT.2 R10.2 | length 113.4
  Top Layer w20: v1(3137,199) HS_FLT.2@3137,260.47
  Bottom Layer w10: R10.2@3137,251.5 R10.2@3138,252.5
  Bottom Layer w30: v1@3137,201 R10.2@3137,251.5
NetHS_OC_2: HS_OC.2 R12.2 | length 115.9
  Top Layer w10: HS_OC.2@3224,258.52 HS_OC.2@3225,257.52
  Top Layer w20: v1(3225,198) HS_OC.2@3225,257.52
  Bottom Layer w10: R12.2@3225,251.5 R12.2@3226,252.5
  Bottom Layer w30: v1(3225,198) R12.2@3225,251.5
NetJ2_2: J2.2 U8.1 | length 722.5
  Bottom Layer w15: U8.1@3522.24,254.61 3574.61,254.61 3626,306 3626,414 3652,440 4099,440 J2.2@4103,436
NetJ2_3: J2.3 U7.2 | length 365.8
  Signal Layer 2 w15: v1(3841,170) 3937,170 J2.3@4103,336
  Bottom Layer w10: v1@3840.84,169.84 v1(3841,170)
  Bottom Layer w12: U7.2@3806,169.84 v1@3840.84,169.84
NetJ3_2: J3.2 U9.5 | length 523.2
  Signal Layer 2 w15: v1(3586,1481) 3665.98,1481.02 J3.2@3914,1233
  Bottom Layer w15: v1(3586,1481) 3587.35,1481 3588.97,1479.39 U9.5@3677.76,1479.39
NetJ3_3: J3.3 U10.2 | length 280.2
  Bottom Layer w12: U10.2@3806,1321.69 3851.32,1321.69 3866,1307 3866,1146.45 3878.52,1133.93 3913.07,1133.93 J3.3@3914,1133
NetL1_2: L1.2 U1.42 | length 102.3
  Top Layer w15: L1.2@1003.63,1710 1003.63,1691.07 1007,1687.7 v1(1039.87,1687.7)
  Bottom Layer w15: v1(1039.87,1687.7) 1057.41,1670.16 1057.41,1667.87 U1.42@1070.58,1654.7
NetL2_2: L2.2 U2.42 | length 106.6
  Top Layer w15: v1(583.37,1691) L2.2@583.37,1750
  Bottom Layer w15: U2.42@556.15,1654.7 556.15,1663.78 v1(583.37,1691)
NetLDO_2: LDO.2 R21.2 | length 108.9
  Top Layer w20: v1(4071,866) LDO.2@4071,913
  Bottom Layer w10: v1(4071,866) 4071,805.5 R21.2@4072,804.5
NetLS_FLT_2: LS_FLT.2 R14.2 | length 121.8
  Top Layer w10: LS_FLT.2@3213,1335.47 LS_FLT.2@3215,1337.47
  Top Layer w20: v1(3215,1277) LS_FLT.2@3215,1337.47
  Bottom Layer w30: v1(3215,1277) R14.2@3215,1335.5
NetLS_OC_2: LS_OC.2 R17.2 | length 119.2
  Top Layer w10: LS_OC.2@3135,1332.52 LS_OC.2@3136,1333.52
  Top Layer w20: v1(3135,1278) LS_OC.2@3135,1332.52
  Bottom Layer w10: R17.2@3132,1340.01 R17.2@3135,1337.01
  Bottom Layer w30: v1(3135,1278) R17.2@3135,1337.01
NetR4_1: R4.1 U5.32 | length 141.1
  Top Layer w15: R4.1@2478.5,837 2512.34,870.84 U5.32@2605.58,870.84
NetR6_1: R6.1 U3.6 | length 2158.1
  Top Layer w10: R6.1@1238.62,1801 R6.1@1239,1801.38 ; U3.6@2706.23,546.25 U3.6@2706.48,546.5
  Top Layer w15: R6.1@1239,1801.38 v1(1239,1831) ; v1(2637,545) 2638.35,545 2639.85,546.5 U3.6@2691.48,546.5
  Signal Layer 1 w15: v1(1239,1831) 1310,1760 1598,1760 2162,1196 2162,954 2551,565 2617,565 v1(2637,545)
NetR15_1: R15.1 U4.6 | length 2370.8
  Top Layer w15: R15.1@708.72,1807 708.72,1823.72 v1(731,1846) ; v1(2639,1616) 2639.25,1615.75 2691.23,1615.75 U4.6@2691.48,1615.5
  Signal Layer 1 w15: v1(731,1846) 731,1987 812.09,2068.09 2051.58,2068.09 2503.68,1616 v1(2639,1616)
NetR18_1: R18.1 U3.5 | length 130.8
  Top Layer w10: R18.1@2562.54,576 R18.1@2567.04,571.5
  Top Layer w15: R18.1@2567.04,571.5 U3.5@2691.48,571.5
NetR19_1: R19.1 U3.13 | length 225.7
  Top Layer w15: U3.13@2908.52,596.5 3054.5,596.5 3100,551 R19.1@3100,535.62
NetR20_1: R20.1 U3.14 | length 379.4
  Top Layer w15: U3.14@2908.52,621.5 3168.74,621.5 R20.1@3253,537.24
NetR25_1: R25.1 U6.32 | length 143.2
  Top Layer w15: R25.1@2478.5,1923 2479.48,1923 2490.68,1934.2 2490.68,1935.19 2515.09,1959.59 U6.32@2606,1959.59
NetR34_1: R34.1 U8.7 | length 862.4
  Top Layer w20: v1(3067,131) R34.1@3067,175
  Signal Layer 2 w15: v1(3067,131) 3095,159 3655,159 3741,245 v1@3741,278.1
  Bottom Layer w12: v1@3736.73,280.2 3738.84,278.1 v1@3741,278.1
  Bottom Layer w15: U8.7@3677.76,280.2 v1@3736.73,280.2
  other v1: 3741,280.1
NetR35_2: R35.2 U8.2 U8.3 | length 428.4
  Bottom Layer w15: U8.2@3522.24,280.2 U8.3@3522.24,305.8 3565.8,305.8 3591.5,331.5 3591.5,566.01 R35.2@3654,628.5
NetR36_1: R36.1 U9.6 U9.7 | length 773.3
  Signal Layer 2 w15: v1(3586,1428) 3557,1399 3557,1043 v1(3587,1013)
  Bottom Layer w15: v1(3586,1428) 3586.2,1428.2 U9.7@3677.76,1428.2 U9.6@3677.76,1453.8
  Bottom Layer w20: v1(3587,1013) 3589,1013 3654,948 R36.1@3654,825.48
NetR38_1: R38.1 U9.3 | length 541.7
  Top Layer w15: R38.1@3035,1373 3036,1374 3078.62,1374 3087.62,1365 v1(3088,1365)
  Signal Layer 2 w15: v1(3088,1365) 3276,1365 3381.1,1470.1 3484.53,1470.1 3487.78,1466.85 v1(3489.13,1466.85)
  Bottom Layer w10: U9.3@3503.78,1453.8 U9.3@3522.24,1453.8
  Bottom Layer w15: v1(3489.13,1466.85) 3502.18,1453.8 U9.3@3503.78,1453.8
NetR39_1: R39.1 U4.13 | length 208.4
  Top Layer w15: U4.13@2904.08,1665.5 3048.5,1665.5 3079.69,1634.31 3079.69,1620.56 R39.1@3084,1616.24
NetR40_1: R40.1 U4.14 | length 365.7
  Top Layer w15: U4.14@2904.08,1690.5 3164.74,1690.5 R40.1@3239,1616.24
NetR41_2: R41.2 U2.49 | length 2242.1
  Top Layer w10: R41.2@2521.46,1635 R41.2@2527.46,1641
  Top Layer w15: v1(2437,1635) R41.2@2521.46,1635
  Signal Layer 1 w15: v1(778.98,1718) 778.98,1719.35 787,1727.37 787,1982 848,2043 2029,2043 v1(2437,1635)
  Bottom Layer w15: U2.49@778.98,1673.4 v1@778.98,1711
NetU7_1: U7.1 U10.3 U10.7 | length 1317.3
  Signal Layer 2 w15: v1(3769.65,190) 3799,219.35 3799,1226 v1(3837,1264)
  Bottom Layer w12: U10.7@3689.76,1321.78 3759.22,1321.78 3778.91,1302.09 U10.3@3796.25,1302.09 ; v1@3770.12,189.53 U7.1@3806,189.53 ; U10.3@3806,1302 3829.97,1302 3837,1294.97 v1(3837,1264)
NetU7_3: U7.3 U7.7 | length 134.1
  Bottom Layer w12: U7.7@3680.02,169.84 3724.16,169.84 3743.84,150.16 U7.3@3806,150.16
OC_H: U1.48 U3.3 | length 2630.5
  Top Layer w15: v1@2637.5,621.5 U3.3@2691.48,621.5
  Signal Layer 1 w15: v1(1266.38,1704.64) 1221.74,1660 1139.1,1660 1114,1685.1 1114,1813 1199,1898 1547,1898 2238,1207 2238,953 2569,622 v1(2637,622)
  Bottom Layer w15: v1(1266.38,1704.64) 1266.38,1703.28 1267.82,1701.84 U1.48@1267.82,1673.4
OC_L: U2.48 U4.4 | length 2573.2
  Top Layer w15: v1(2616,1667) 2617.35,1667 2618.85,1665.5 U4.4@2691.48,1665.5
  Signal Layer 1 w15: v1(753.39,1706.08) 735.42,1706.08 701,1740.5 701,2010 787,2096 2068,2096 2497,1667 v1(2616,1667)
  Bottom Layer w15: U2.48@753.39,1673.4 v1@753.39,1706
PWM_Bot: J1.1 J3.1 U10.1 | length 686.1
  Bottom Layer w12: U10.1@3806,1341.37 3905.63,1341.37 J3.1@3914,1333
  Bottom Layer w20: J3.1@3914,1333 4415,1333 4460,1288 J1.1@4460,1278
PWM_Top: J2.1 J4.1 | length 379.4
  Top Layer w50: J2.1@4103,536 4145,578 J4.1@4465,578
SW: C1.2 C2.2 C3.1 C5.1 C10.2 C28.2 C29.2 C42.2 D1.2 ISO15VSW.1 L1.1 L4.1 pad.3@2011,1084 R2.1 R24.2 TP1.1 U1.17 U1.18 U1.19 U1.20 U1.21 U1.22 U1.23 U1.24 U1.25 U1.26 U1.27 U1.28 U1.29 U1.30 U1.31 U1.32 U1.33 U1.34 U1.35 U1.36 U1.37 U1.38 U1.39 U2.1 U2.2 U2.3 U2.4 U2.5 U2.6 U2.7 U2.8 U2.9 U2.10 U2.11 U2.12 U2.13 U2.14 U2.15 U2.16 U3.2 U3.8 | length 358.5
  Top Layer w10: C10.2@2608.62,647 2612,650.38 C10.2@2615.88,646.5
  Top Layer w15: v1@1463.96,1815.04 1494.21,1784.79 R2.1@1558.39,1784.79 ; v1(2554,494) v1@2582,494 ; v1(2581,647) C10.2@2608.62,647 ; v1(2583,493) 2583.96,493.96 2587.49,493.96 2588.54,495 2609.65,495 2609.69,494.96 2611.96,494.96 v1@2612,495 ; v1@2612.96,494.96 2616.49,494.96 2616.54,495 2631.46,495 2631.51,495.04 2635.96,495.04 v1(2637,496) ; C10.2@2615.88,646.5 U3.2@2691.48,646.5 ; v1@2637.5,496.5 U3.8@2691.48,496.5 ; U3.8@2706.23,496.75 U3.8@2706.48,496.5
  Bottom Layer w50: v2(1165.35,953) v2@1166.35,954
  other v1: 2612,494 908,1084 938,1084 968,1084 998,1084 1028,1084 1058,1084 1088,1084 1118,1084 1148,1084 1178,1084 1208,1084 953,1109 983,1109 1013,1109 1043,1109 1073,1109 1103,1109 1133,1109 1163,1109 1193,1109 1223,1109 968,1134 998,1134 1028,1134 1058,1134 1088,1134 1118,1134 1148,1134 1178,1134 1208,1134 983,1159 1013,1159 1043,1159 1073,1159 1103,1159 1133,1159 1163,1159 1193,1159 1223,1159 1671,1310.5 1636,1325.5 1671,1357 1636,1372 1671,1403.5 1636,1418.5 1671,1450 1636,1465 1671,1496.5 1636,1511.5 1671,1543 1636,1558 1164.14,1606 1192.57,1606 1221,1606 1249.43,1606 1277.86,1606 1306.29,1606 1334.71,1606 1192,1636 1221,1636 1249,1636 1463,1816
TEMP_H: R18.2 U1.49 | length 1898
  Top Layer w10: R18.2@2504.46,575 R18.2@2505.46,576
  Top Layer w15: v1(2448,575) R18.2@2504.46,575
  Signal Layer 1 w15: v1(1293,1718) 1293,1675.79 1301.79,1667 1601,1667 2077,1191 2077,946 v1@2447.04,575.96
  Bottom Layer w15: v1(1293,1718) 1293.41,1717.59 U1.49@1293.41,1673.4
TEMP_L: R41.1 U4.5 | length 99.4
  Top Layer w10: R41.1@2593.54,1637 R41.1@2597.04,1640.5
  Top Layer w15: R41.1@2597.04,1640.5 U4.5@2691.48,1640.5
Top_FET_FAULT: C40.1 C50.1 pad.1@3123,427 R10.1 R19.2 U9.1 | length 1587.3
  Top Layer w20: R19.2@3100,488.38 3100,456 pad.1@3123,427 ; v1(3140,375) 3123,392 pad.1@3123,427 ; C40.1@3150,488.38 3150,458 pad.1@3123,427
  Signal Layer 2 w15: v1(3140,375) 3179,375 3464,660 3464,1387 v1(3447,1404)
  Bottom Layer w10: v1(3447,1404) v1@3447.69,1403.31 ; U9.1@3521.55,1403.31 U9.1@3522.24,1402.61
  Bottom Layer w15: v1@3447.69,1403.31 U9.1@3521.55,1403.31
  Bottom Layer w30: R10.1@3140,317.5 v1(3140,375) C50.1@3140,436
Top_FET_OC: C39.1 C51.1 pad.1@3223,428 R12.1 R20.2 U9.2 | length 1583.6
  Top Layer w20: C39.1@3200,488.38 3200,451 pad.1@3223,428 ; v1(3224,375) 3223.5,375.5 3223.5,427.5 pad.1@3223,428 ; R20.2@3253,490 3253,449 3232,428 pad.1@3223,428
  Signal Layer 2 w15: v1(3224,375) 3258,375 3512,629 3512,1392 v1(3472,1432)
  Bottom Layer w15: v1(3472,1432) 3473.35,1432 3477.15,1428.2 U9.2@3522.24,1428.2
  Bottom Layer w30: v1@3225,376 C51.1@3225,434.5 ; R12.1@3226,315.5 v1@3226,373
Top_FET_PWM: pad.1@3052,426 R7.1 R34.2 Top_FET_PWM.1 | length 358.7
  Top Layer w20: R34.2@3011,175 2977,209 2977,296 3052,371 pad.1@3052,426 R7.1@3050.5,488.5
Top_FET_TEMP: U3.12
